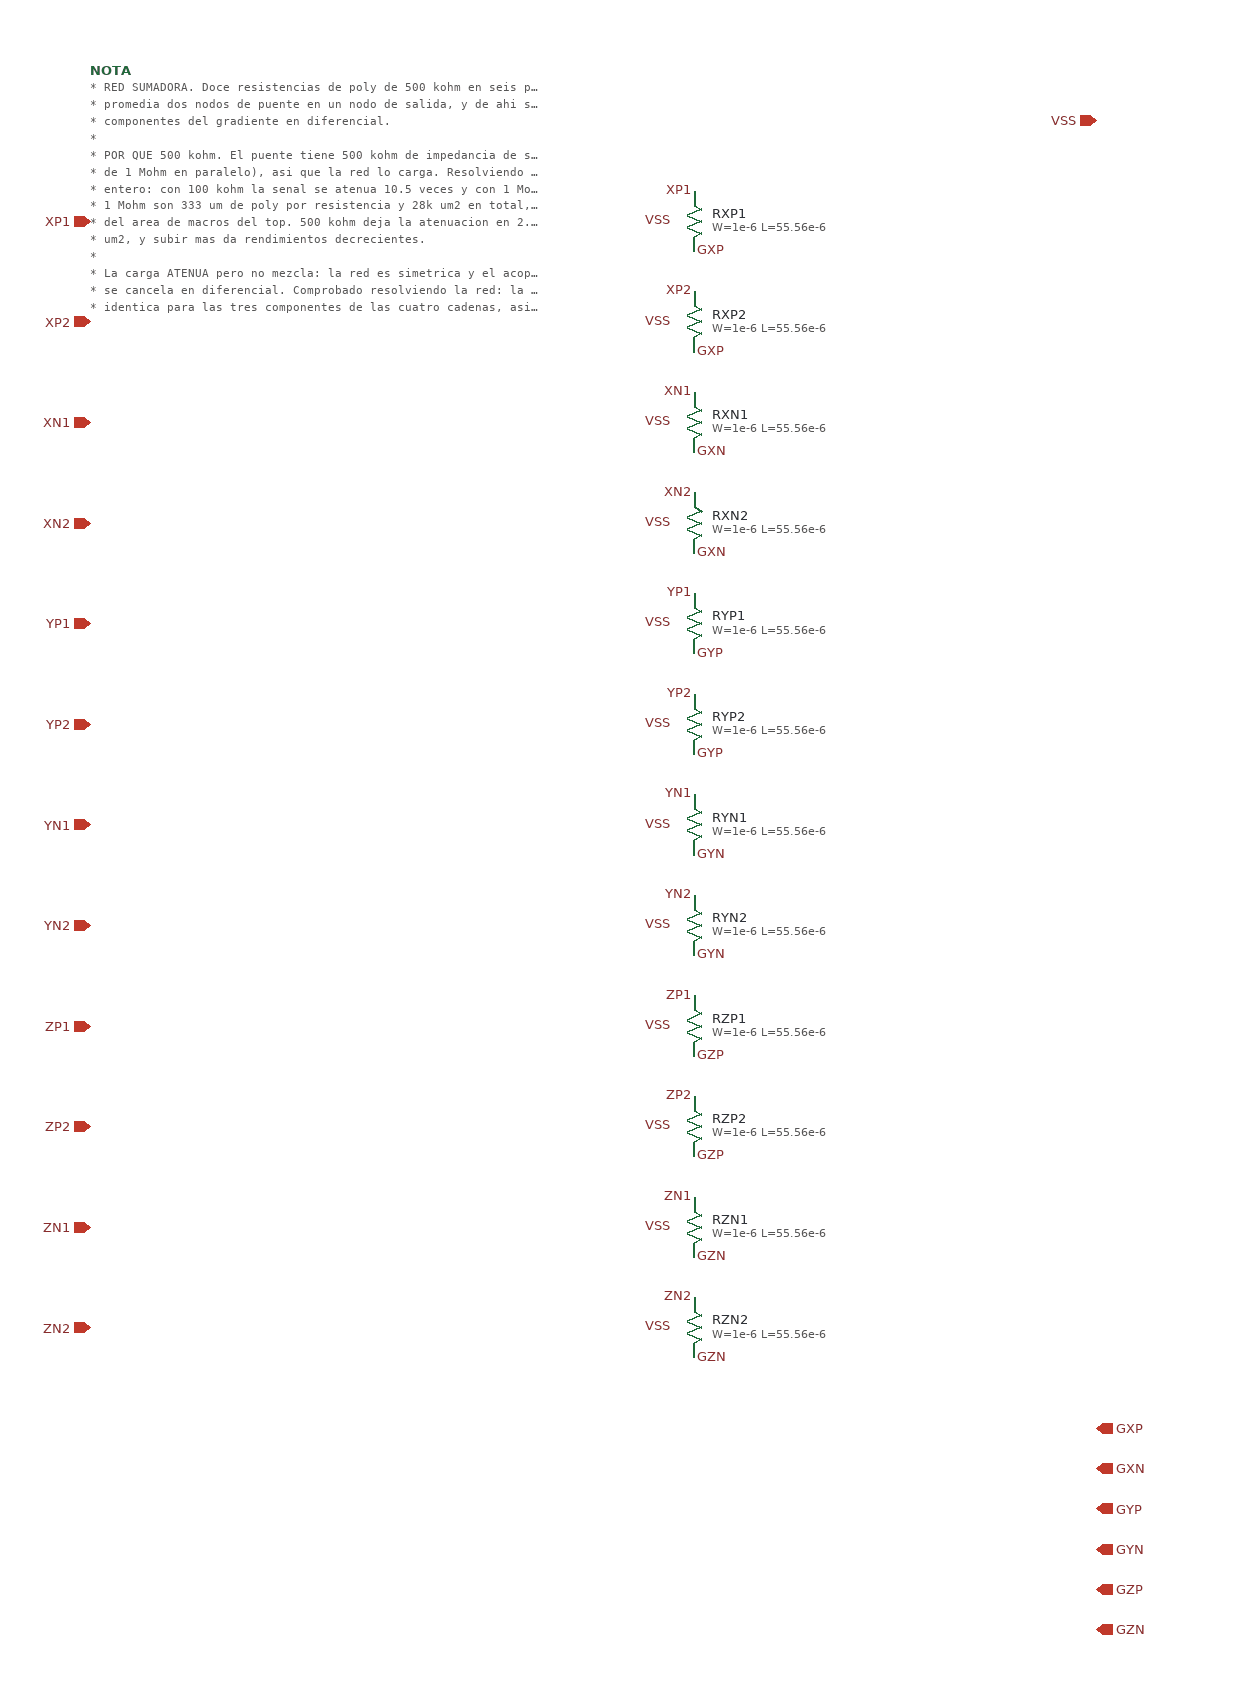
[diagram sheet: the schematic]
v {xschem version=3.4.8RC file_version=1.3}
G {}
K {}
V {}
S {}
F {}
E {}
C {symbols/ppolyf_u_3k.sym} 200 -600 0 0 {name=RXP1
W=1e-6
L=55.56e-6
model=ppolyf_u_3k
spiceprefix=X
m=1
s=3
format="@spiceprefix@name @pinlist @model r_width=@W r_length=@L m=@m s=@s"}
C {devices/lab_pin.sym} 200 -630 0 0 {name=pXP1a sig_type=std_logic lab=XP1}
C {devices/lab_pin.sym} 200 -570 2 0 {name=pXP1b sig_type=std_logic lab=GXP}
C {devices/lab_pin.sym} 180 -600 0 0 {name=pXP1c sig_type=std_logic lab=VSS}
C {ipin.sym} -400 -600 0 0 {name=iXP1 lab=XP1}
C {symbols/ppolyf_u_3k.sym} 200 -500 0 0 {name=RXP2
W=1e-6
L=55.56e-6
model=ppolyf_u_3k
spiceprefix=X
m=1
s=3
format="@spiceprefix@name @pinlist @model r_width=@W r_length=@L m=@m s=@s"}
C {devices/lab_pin.sym} 200 -530 0 0 {name=pXP2a sig_type=std_logic lab=XP2}
C {devices/lab_pin.sym} 200 -470 2 0 {name=pXP2b sig_type=std_logic lab=GXP}
C {devices/lab_pin.sym} 180 -500 0 0 {name=pXP2c sig_type=std_logic lab=VSS}
C {ipin.sym} -400 -500 0 0 {name=iXP2 lab=XP2}
C {symbols/ppolyf_u_3k.sym} 200 -400 0 0 {name=RXN1
W=1e-6
L=55.56e-6
model=ppolyf_u_3k
spiceprefix=X
m=1
s=3
format="@spiceprefix@name @pinlist @model r_width=@W r_length=@L m=@m s=@s"}
C {devices/lab_pin.sym} 200 -430 0 0 {name=pXN1a sig_type=std_logic lab=XN1}
C {devices/lab_pin.sym} 200 -370 2 0 {name=pXN1b sig_type=std_logic lab=GXN}
C {devices/lab_pin.sym} 180 -400 0 0 {name=pXN1c sig_type=std_logic lab=VSS}
C {ipin.sym} -400 -400 0 0 {name=iXN1 lab=XN1}
C {symbols/ppolyf_u_3k.sym} 200 -300 0 0 {name=RXN2
W=1e-6
L=55.56e-6
model=ppolyf_u_3k
spiceprefix=X
m=1
s=3
format="@spiceprefix@name @pinlist @model r_width=@W r_length=@L m=@m s=@s"}
C {devices/lab_pin.sym} 200 -330 0 0 {name=pXN2a sig_type=std_logic lab=XN2}
C {devices/lab_pin.sym} 200 -270 2 0 {name=pXN2b sig_type=std_logic lab=GXN}
C {devices/lab_pin.sym} 180 -300 0 0 {name=pXN2c sig_type=std_logic lab=VSS}
C {ipin.sym} -400 -300 0 0 {name=iXN2 lab=XN2}
C {symbols/ppolyf_u_3k.sym} 200 -200 0 0 {name=RYP1
W=1e-6
L=55.56e-6
model=ppolyf_u_3k
spiceprefix=X
m=1
s=3
format="@spiceprefix@name @pinlist @model r_width=@W r_length=@L m=@m s=@s"}
C {devices/lab_pin.sym} 200 -230 0 0 {name=pYP1a sig_type=std_logic lab=YP1}
C {devices/lab_pin.sym} 200 -170 2 0 {name=pYP1b sig_type=std_logic lab=GYP}
C {devices/lab_pin.sym} 180 -200 0 0 {name=pYP1c sig_type=std_logic lab=VSS}
C {ipin.sym} -400 -200 0 0 {name=iYP1 lab=YP1}
C {symbols/ppolyf_u_3k.sym} 200 -100 0 0 {name=RYP2
W=1e-6
L=55.56e-6
model=ppolyf_u_3k
spiceprefix=X
m=1
s=3
format="@spiceprefix@name @pinlist @model r_width=@W r_length=@L m=@m s=@s"}
C {devices/lab_pin.sym} 200 -130 0 0 {name=pYP2a sig_type=std_logic lab=YP2}
C {devices/lab_pin.sym} 200 -70 2 0 {name=pYP2b sig_type=std_logic lab=GYP}
C {devices/lab_pin.sym} 180 -100 0 0 {name=pYP2c sig_type=std_logic lab=VSS}
C {ipin.sym} -400 -100 0 0 {name=iYP2 lab=YP2}
C {symbols/ppolyf_u_3k.sym} 200 0 0 0 {name=RYN1
W=1e-6
L=55.56e-6
model=ppolyf_u_3k
spiceprefix=X
m=1
s=3
format="@spiceprefix@name @pinlist @model r_width=@W r_length=@L m=@m s=@s"}
C {devices/lab_pin.sym} 200 -30 0 0 {name=pYN1a sig_type=std_logic lab=YN1}
C {devices/lab_pin.sym} 200 30 2 0 {name=pYN1b sig_type=std_logic lab=GYN}
C {devices/lab_pin.sym} 180 0 0 0 {name=pYN1c sig_type=std_logic lab=VSS}
C {ipin.sym} -400 0 0 0 {name=iYN1 lab=YN1}
C {symbols/ppolyf_u_3k.sym} 200 100 0 0 {name=RYN2
W=1e-6
L=55.56e-6
model=ppolyf_u_3k
spiceprefix=X
m=1
s=3
format="@spiceprefix@name @pinlist @model r_width=@W r_length=@L m=@m s=@s"}
C {devices/lab_pin.sym} 200 70 0 0 {name=pYN2a sig_type=std_logic lab=YN2}
C {devices/lab_pin.sym} 200 130 2 0 {name=pYN2b sig_type=std_logic lab=GYN}
C {devices/lab_pin.sym} 180 100 0 0 {name=pYN2c sig_type=std_logic lab=VSS}
C {ipin.sym} -400 100 0 0 {name=iYN2 lab=YN2}
C {symbols/ppolyf_u_3k.sym} 200 200 0 0 {name=RZP1
W=1e-6
L=55.56e-6
model=ppolyf_u_3k
spiceprefix=X
m=1
s=3
format="@spiceprefix@name @pinlist @model r_width=@W r_length=@L m=@m s=@s"}
C {devices/lab_pin.sym} 200 170 0 0 {name=pZP1a sig_type=std_logic lab=ZP1}
C {devices/lab_pin.sym} 200 230 2 0 {name=pZP1b sig_type=std_logic lab=GZP}
C {devices/lab_pin.sym} 180 200 0 0 {name=pZP1c sig_type=std_logic lab=VSS}
C {ipin.sym} -400 200 0 0 {name=iZP1 lab=ZP1}
C {symbols/ppolyf_u_3k.sym} 200 300 0 0 {name=RZP2
W=1e-6
L=55.56e-6
model=ppolyf_u_3k
spiceprefix=X
m=1
s=3
format="@spiceprefix@name @pinlist @model r_width=@W r_length=@L m=@m s=@s"}
C {devices/lab_pin.sym} 200 270 0 0 {name=pZP2a sig_type=std_logic lab=ZP2}
C {devices/lab_pin.sym} 200 330 2 0 {name=pZP2b sig_type=std_logic lab=GZP}
C {devices/lab_pin.sym} 180 300 0 0 {name=pZP2c sig_type=std_logic lab=VSS}
C {ipin.sym} -400 300 0 0 {name=iZP2 lab=ZP2}
C {symbols/ppolyf_u_3k.sym} 200 400 0 0 {name=RZN1
W=1e-6
L=55.56e-6
model=ppolyf_u_3k
spiceprefix=X
m=1
s=3
format="@spiceprefix@name @pinlist @model r_width=@W r_length=@L m=@m s=@s"}
C {devices/lab_pin.sym} 200 370 0 0 {name=pZN1a sig_type=std_logic lab=ZN1}
C {devices/lab_pin.sym} 200 430 2 0 {name=pZN1b sig_type=std_logic lab=GZN}
C {devices/lab_pin.sym} 180 400 0 0 {name=pZN1c sig_type=std_logic lab=VSS}
C {ipin.sym} -400 400 0 0 {name=iZN1 lab=ZN1}
C {symbols/ppolyf_u_3k.sym} 200 500 0 0 {name=RZN2
W=1e-6
L=55.56e-6
model=ppolyf_u_3k
spiceprefix=X
m=1
s=3
format="@spiceprefix@name @pinlist @model r_width=@W r_length=@L m=@m s=@s"}
C {devices/lab_pin.sym} 200 470 0 0 {name=pZN2a sig_type=std_logic lab=ZN2}
C {devices/lab_pin.sym} 200 530 2 0 {name=pZN2b sig_type=std_logic lab=GZN}
C {devices/lab_pin.sym} 180 500 0 0 {name=pZN2c sig_type=std_logic lab=VSS}
C {ipin.sym} -400 500 0 0 {name=iZN2 lab=ZN2}
C {opin.sym} 600 600 0 0 {name=oGXP lab=GXP}
C {opin.sym} 600 640 0 0 {name=oGXN lab=GXN}
C {opin.sym} 600 680 0 0 {name=oGYP lab=GYP}
C {opin.sym} 600 720 0 0 {name=oGYN lab=GYN}
C {opin.sym} 600 760 0 0 {name=oGZP lab=GZP}
C {opin.sym} 600 800 0 0 {name=oGZN lab=GZN}
C {iopin.sym} 600 -700 0 0 {name=pVSS lab=VSS}
C {devices/code_shown.sym} -400 -750 0 0 {name=NOTA only_toplevel=false
value="
* RED SUMADORA. Doce resistencias de poly de 500 kohm en seis pares: cada par
* promedia dos nodos de puente en un nodo de salida, y de ahi salen las tres
* componentes del gradiente en diferencial.
*
* POR QUE 500 kohm. El puente tiene 500 kohm de impedancia de salida (dos ramas
* de 1 Mohm en paralelo), asi que la red lo carga. Resolviendo el circuito
* entero: con 100 kohm la senal se atenua 10.5 veces y con 1 Mohm solo 1.5, pero
* 1 Mohm son 333 um de poly por resistencia y 28k um2 en total, casi un tercio
* del area de macros del top. 500 kohm deja la atenuacion en 2.5 veces por 14k
* um2, y subir mas da rendimientos decrecientes.
*
* La carga ATENUA pero no mezcla: la red es simetrica y el acoplo entre puentes
* se cancela en diferencial. Comprobado resolviendo la red: la ganancia sale
* identica para las tres componentes de las cuatro cadenas, asi que tampoco mete
* anisotropia por la puerta de atras.
*
* Que sensor va a cada entrada, y con que signo, lo decide el TOP. Los cuatro
* trios usan pares distintos de sensores, pero la FORMA es la misma -- dos
* sensores por componente con peso +-0.5 -- asi que esta celda sirve para los
* cuatro y el signo se hace eligiendo si va la pata P o la N.
"}
